VERSION 5.7 ;
  NOWIREEXTENSIONATPIN ON ;
  DIVIDERCHAR "/" ;
  BUSBITCHARS "[]" ;
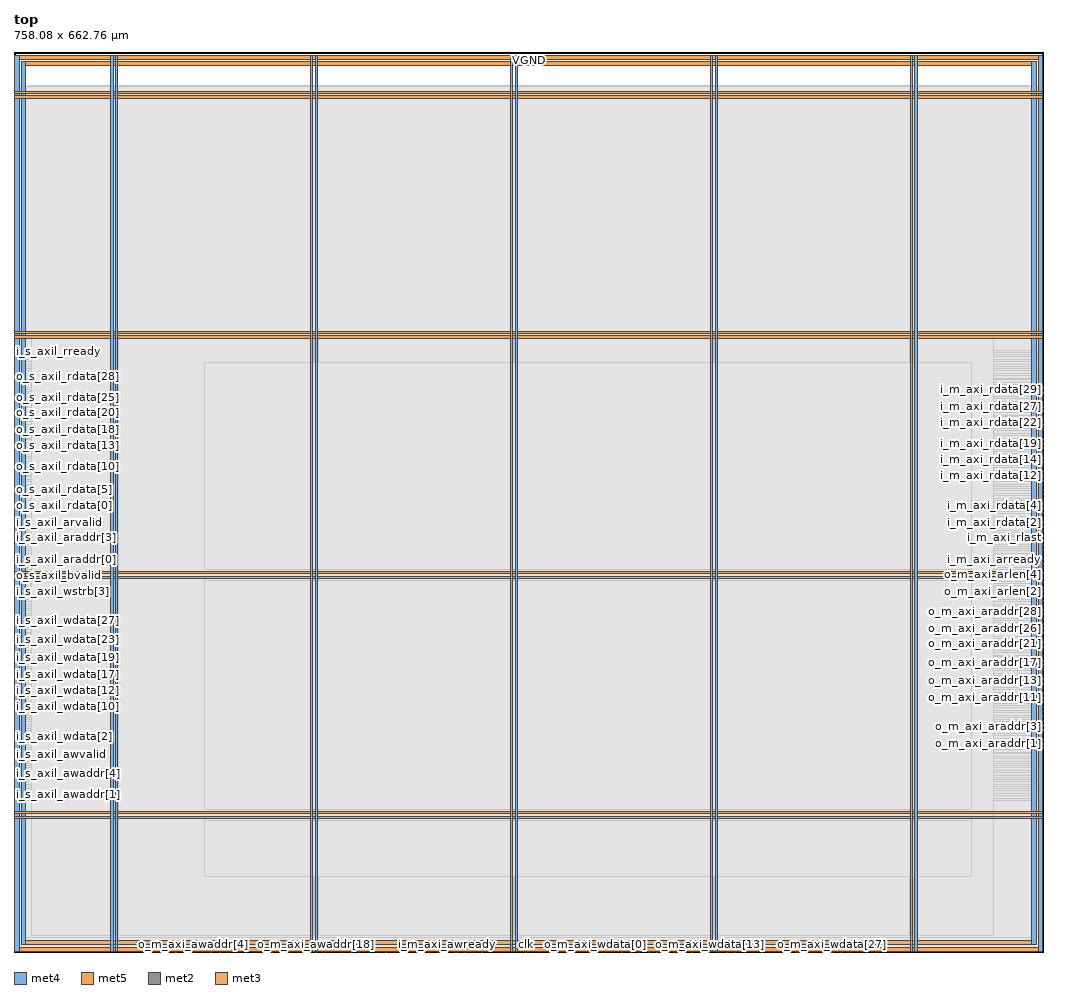
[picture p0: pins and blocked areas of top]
MACRO top
  CLASS BLOCK ;
  FOREIGN top ;
  ORIGIN 0.000 0.000 ;
  SIZE 758.080 BY 662.760 ;
  PIN VGND
    DIRECTION INOUT ;
    USE GROUND ;
    PORT
      LAYER met4 ;
        RECT 0.640 0.480 3.740 660.480 ;
    END
    PORT
      LAYER met4 ;
        RECT 754.340 0.480 757.440 660.480 ;
    END
    PORT
      LAYER met5 ;
        RECT 0.640 0.480 757.440 3.580 ;
    END
    PORT
      LAYER met5 ;
        RECT 0.640 657.380 757.440 660.480 ;
    END
    PORT
      LAYER met4 ;
        RECT 74.675 0.480 76.275 660.480 ;
    END
    PORT
      LAYER met4 ;
        RECT 221.875 0.480 223.475 660.480 ;
    END
    PORT
      LAYER met4 ;
        RECT 369.075 0.480 370.675 660.480 ;
    END
    PORT
      LAYER met4 ;
        RECT 516.275 0.480 517.875 660.480 ;
    END
    PORT
      LAYER met4 ;
        RECT 663.475 0.480 665.075 660.480 ;
    END
    PORT
      LAYER met5 ;
        RECT 0.640 101.780 757.440 103.380 ;
    END
    PORT
      LAYER met5 ;
        RECT 0.640 278.580 757.440 280.180 ;
    END
    PORT
      LAYER met5 ;
        RECT 0.640 455.380 757.440 456.980 ;
    END
    PORT
      LAYER met5 ;
        RECT 0.640 632.180 757.440 633.780 ;
    END
  END VGND
  PIN VPWR
    DIRECTION INOUT ;
    USE POWER ;
    PORT
      LAYER met4 ;
        RECT 5.440 5.280 8.540 655.680 ;
    END
    PORT
      LAYER met4 ;
        RECT 749.540 5.280 752.640 655.680 ;
    END
    PORT
      LAYER met5 ;
        RECT 5.440 5.280 752.640 8.380 ;
    END
    PORT
      LAYER met5 ;
        RECT 5.440 652.580 752.640 655.680 ;
    END
    PORT
      LAYER met4 ;
        RECT 71.375 0.480 72.975 660.480 ;
    END
    PORT
      LAYER met4 ;
        RECT 218.575 0.480 220.175 660.480 ;
    END
    PORT
      LAYER met4 ;
        RECT 365.775 0.480 367.375 660.480 ;
    END
    PORT
      LAYER met4 ;
        RECT 512.975 0.480 514.575 660.480 ;
    END
    PORT
      LAYER met4 ;
        RECT 660.175 0.480 661.775 660.480 ;
    END
    PORT
      LAYER met5 ;
        RECT 0.640 98.480 757.440 100.080 ;
    END
    PORT
      LAYER met5 ;
        RECT 0.640 275.280 757.440 276.880 ;
    END
    PORT
      LAYER met5 ;
        RECT 0.640 452.080 757.440 453.680 ;
    END
    PORT
      LAYER met5 ;
        RECT 0.640 628.880 757.440 630.480 ;
    END
  END VPWR
  PIN clk
    DIRECTION INPUT ;
    USE SIGNAL ;
    ANTENNAGATEAREA 1.704000 ;
    PORT
      LAYER met2 ;
        RECT 376.830 0.000 377.110 0.280 ;
    END
  END clk
  PIN i_m_axi_arready
    DIRECTION INPUT ;
    USE SIGNAL ;
    ANTENNAGATEAREA 0.196500 ;
    PORT
      LAYER met3 ;
        RECT 757.480 289.040 758.080 289.640 ;
    END
  END i_m_axi_arready
  PIN i_m_axi_awready
    DIRECTION INPUT ;
    USE SIGNAL ;
    ANTENNAGATEAREA 0.196500 ;
    PORT
      LAYER met2 ;
        RECT 318.870 0.000 319.150 0.280 ;
    END
  END i_m_axi_awready
  PIN i_m_axi_bresp[0]
    DIRECTION INPUT ;
    USE SIGNAL ;
    ANTENNAGATEAREA 0.196500 ;
    PORT
      LAYER met2 ;
        RECT 325.310 0.000 325.590 0.280 ;
    END
  END i_m_axi_bresp[0]
  PIN i_m_axi_bresp[1]
    DIRECTION INPUT ;
    USE SIGNAL ;
    ANTENNAGATEAREA 0.196500 ;
    PORT
      LAYER met2 ;
        RECT 331.750 0.000 332.030 0.280 ;
    END
  END i_m_axi_bresp[1]
  PIN i_m_axi_bvalid
    DIRECTION INPUT ;
    USE SIGNAL ;
    ANTENNAGATEAREA 0.196500 ;
    PORT
      LAYER met2 ;
        RECT 338.190 0.000 338.470 0.280 ;
    END
  END i_m_axi_bvalid
  PIN i_m_axi_rdata[0]
    DIRECTION INPUT ;
    USE SIGNAL ;
    ANTENNAGATEAREA 0.196500 ;
    PORT
      LAYER met3 ;
        RECT 757.480 309.440 758.080 310.040 ;
    END
  END i_m_axi_rdata[0]
  PIN i_m_axi_rdata[10]
    DIRECTION INPUT ;
    USE SIGNAL ;
    ANTENNAGATEAREA 0.196500 ;
    PORT
      LAYER met3 ;
        RECT 757.480 343.440 758.080 344.040 ;
    END
  END i_m_axi_rdata[10]
  PIN i_m_axi_rdata[11]
    DIRECTION INPUT ;
    USE SIGNAL ;
    ANTENNAGATEAREA 0.196500 ;
    PORT
      LAYER met3 ;
        RECT 757.480 346.840 758.080 347.440 ;
    END
  END i_m_axi_rdata[11]
  PIN i_m_axi_rdata[12]
    DIRECTION INPUT ;
    USE SIGNAL ;
    ANTENNAGATEAREA 0.196500 ;
    PORT
      LAYER met3 ;
        RECT 757.480 350.240 758.080 350.840 ;
    END
  END i_m_axi_rdata[12]
  PIN i_m_axi_rdata[13]
    DIRECTION INPUT ;
    USE SIGNAL ;
    ANTENNAGATEAREA 0.196500 ;
    PORT
      LAYER met3 ;
        RECT 757.480 353.640 758.080 354.240 ;
    END
  END i_m_axi_rdata[13]
  PIN i_m_axi_rdata[14]
    DIRECTION INPUT ;
    USE SIGNAL ;
    ANTENNAGATEAREA 0.196500 ;
    PORT
      LAYER met3 ;
        RECT 757.480 357.040 758.080 357.640 ;
    END
  END i_m_axi_rdata[14]
  PIN i_m_axi_rdata[15]
    DIRECTION INPUT ;
    USE SIGNAL ;
    ANTENNAGATEAREA 0.196500 ;
    PORT
      LAYER met3 ;
        RECT 757.480 360.440 758.080 361.040 ;
    END
  END i_m_axi_rdata[15]
  PIN i_m_axi_rdata[16]
    DIRECTION INPUT ;
    USE SIGNAL ;
    ANTENNAGATEAREA 0.196500 ;
    PORT
      LAYER met3 ;
        RECT 757.480 363.840 758.080 364.440 ;
    END
  END i_m_axi_rdata[16]
  PIN i_m_axi_rdata[17]
    DIRECTION INPUT ;
    USE SIGNAL ;
    ANTENNAGATEAREA 0.196500 ;
    PORT
      LAYER met3 ;
        RECT 757.480 367.240 758.080 367.840 ;
    END
  END i_m_axi_rdata[17]
  PIN i_m_axi_rdata[18]
    DIRECTION INPUT ;
    USE SIGNAL ;
    ANTENNAGATEAREA 0.196500 ;
    PORT
      LAYER met3 ;
        RECT 757.480 370.640 758.080 371.240 ;
    END
  END i_m_axi_rdata[18]
  PIN i_m_axi_rdata[19]
    DIRECTION INPUT ;
    USE SIGNAL ;
    ANTENNAGATEAREA 0.196500 ;
    PORT
      LAYER met3 ;
        RECT 757.480 374.040 758.080 374.640 ;
    END
  END i_m_axi_rdata[19]
  PIN i_m_axi_rdata[1]
    DIRECTION INPUT ;
    USE SIGNAL ;
    ANTENNAGATEAREA 0.196500 ;
    PORT
      LAYER met3 ;
        RECT 757.480 312.840 758.080 313.440 ;
    END
  END i_m_axi_rdata[1]
  PIN i_m_axi_rdata[20]
    DIRECTION INPUT ;
    USE SIGNAL ;
    ANTENNAGATEAREA 0.196500 ;
    PORT
      LAYER met3 ;
        RECT 757.480 377.440 758.080 378.040 ;
    END
  END i_m_axi_rdata[20]
  PIN i_m_axi_rdata[21]
    DIRECTION INPUT ;
    USE SIGNAL ;
    ANTENNAGATEAREA 0.196500 ;
    PORT
      LAYER met3 ;
        RECT 757.480 380.840 758.080 381.440 ;
    END
  END i_m_axi_rdata[21]
  PIN i_m_axi_rdata[22]
    DIRECTION INPUT ;
    USE SIGNAL ;
    ANTENNAGATEAREA 0.196500 ;
    PORT
      LAYER met3 ;
        RECT 757.480 384.240 758.080 384.840 ;
    END
  END i_m_axi_rdata[22]
  PIN i_m_axi_rdata[23]
    DIRECTION INPUT ;
    USE SIGNAL ;
    ANTENNAGATEAREA 0.196500 ;
    PORT
      LAYER met3 ;
        RECT 757.480 387.640 758.080 388.240 ;
    END
  END i_m_axi_rdata[23]
  PIN i_m_axi_rdata[24]
    DIRECTION INPUT ;
    USE SIGNAL ;
    ANTENNAGATEAREA 0.196500 ;
    PORT
      LAYER met3 ;
        RECT 757.480 391.040 758.080 391.640 ;
    END
  END i_m_axi_rdata[24]
  PIN i_m_axi_rdata[25]
    DIRECTION INPUT ;
    USE SIGNAL ;
    ANTENNAGATEAREA 0.196500 ;
    PORT
      LAYER met3 ;
        RECT 757.480 394.440 758.080 395.040 ;
    END
  END i_m_axi_rdata[25]
  PIN i_m_axi_rdata[26]
    DIRECTION INPUT ;
    USE SIGNAL ;
    ANTENNAGATEAREA 0.196500 ;
    PORT
      LAYER met3 ;
        RECT 757.480 397.840 758.080 398.440 ;
    END
  END i_m_axi_rdata[26]
  PIN i_m_axi_rdata[27]
    DIRECTION INPUT ;
    USE SIGNAL ;
    ANTENNAGATEAREA 0.196500 ;
    PORT
      LAYER met3 ;
        RECT 757.480 401.240 758.080 401.840 ;
    END
  END i_m_axi_rdata[27]
  PIN i_m_axi_rdata[28]
    DIRECTION INPUT ;
    USE SIGNAL ;
    ANTENNAGATEAREA 0.196500 ;
    PORT
      LAYER met3 ;
        RECT 757.480 404.640 758.080 405.240 ;
    END
  END i_m_axi_rdata[28]
  PIN i_m_axi_rdata[29]
    DIRECTION INPUT ;
    USE SIGNAL ;
    ANTENNAGATEAREA 0.196500 ;
    PORT
      LAYER met3 ;
        RECT 757.480 408.040 758.080 408.640 ;
    END
  END i_m_axi_rdata[29]
  PIN i_m_axi_rdata[2]
    DIRECTION INPUT ;
    USE SIGNAL ;
    ANTENNAGATEAREA 0.196500 ;
    PORT
      LAYER met3 ;
        RECT 757.480 316.240 758.080 316.840 ;
    END
  END i_m_axi_rdata[2]
  PIN i_m_axi_rdata[30]
    DIRECTION INPUT ;
    USE SIGNAL ;
    ANTENNAGATEAREA 0.196500 ;
    PORT
      LAYER met3 ;
        RECT 757.480 411.440 758.080 412.040 ;
    END
  END i_m_axi_rdata[30]
  PIN i_m_axi_rdata[31]
    DIRECTION INPUT ;
    USE SIGNAL ;
    ANTENNAGATEAREA 0.196500 ;
    PORT
      LAYER met3 ;
        RECT 757.480 414.840 758.080 415.440 ;
    END
  END i_m_axi_rdata[31]
  PIN i_m_axi_rdata[3]
    DIRECTION INPUT ;
    USE SIGNAL ;
    ANTENNAGATEAREA 0.196500 ;
    PORT
      LAYER met3 ;
        RECT 757.480 319.640 758.080 320.240 ;
    END
  END i_m_axi_rdata[3]
  PIN i_m_axi_rdata[4]
    DIRECTION INPUT ;
    USE SIGNAL ;
    ANTENNAGATEAREA 0.196500 ;
    PORT
      LAYER met3 ;
        RECT 757.480 323.040 758.080 323.640 ;
    END
  END i_m_axi_rdata[4]
  PIN i_m_axi_rdata[5]
    DIRECTION INPUT ;
    USE SIGNAL ;
    ANTENNAGATEAREA 0.196500 ;
    PORT
      LAYER met3 ;
        RECT 757.480 326.440 758.080 327.040 ;
    END
  END i_m_axi_rdata[5]
  PIN i_m_axi_rdata[6]
    DIRECTION INPUT ;
    USE SIGNAL ;
    ANTENNAGATEAREA 0.196500 ;
    PORT
      LAYER met3 ;
        RECT 757.480 329.840 758.080 330.440 ;
    END
  END i_m_axi_rdata[6]
  PIN i_m_axi_rdata[7]
    DIRECTION INPUT ;
    USE SIGNAL ;
    ANTENNAGATEAREA 0.196500 ;
    PORT
      LAYER met3 ;
        RECT 757.480 333.240 758.080 333.840 ;
    END
  END i_m_axi_rdata[7]
  PIN i_m_axi_rdata[8]
    DIRECTION INPUT ;
    USE SIGNAL ;
    ANTENNAGATEAREA 0.196500 ;
    PORT
      LAYER met3 ;
        RECT 757.480 336.640 758.080 337.240 ;
    END
  END i_m_axi_rdata[8]
  PIN i_m_axi_rdata[9]
    DIRECTION INPUT ;
    USE SIGNAL ;
    ANTENNAGATEAREA 0.196500 ;
    PORT
      LAYER met3 ;
        RECT 757.480 340.040 758.080 340.640 ;
    END
  END i_m_axi_rdata[9]
  PIN i_m_axi_rlast
    DIRECTION INPUT ;
    USE SIGNAL ;
    ANTENNAGATEAREA 0.196500 ;
    PORT
      LAYER met3 ;
        RECT 757.480 299.240 758.080 299.840 ;
    END
  END i_m_axi_rlast
  PIN i_m_axi_rresp[0]
    DIRECTION INPUT ;
    USE SIGNAL ;
    ANTENNAGATEAREA 0.196500 ;
    PORT
      LAYER met3 ;
        RECT 757.480 302.640 758.080 303.240 ;
    END
  END i_m_axi_rresp[0]
  PIN i_m_axi_rresp[1]
    DIRECTION INPUT ;
    USE SIGNAL ;
    ANTENNAGATEAREA 0.196500 ;
    PORT
      LAYER met3 ;
        RECT 757.480 306.040 758.080 306.640 ;
    END
  END i_m_axi_rresp[1]
  PIN i_m_axi_rvalid
    DIRECTION INPUT ;
    USE SIGNAL ;
    ANTENNAGATEAREA 0.196500 ;
    PORT
      LAYER met3 ;
        RECT 757.480 295.840 758.080 296.440 ;
    END
  END i_m_axi_rvalid
  PIN i_m_axi_wready
    DIRECTION INPUT ;
    USE SIGNAL ;
    ANTENNAGATEAREA 0.196500 ;
    PORT
      LAYER met2 ;
        RECT 647.310 0.000 647.590 0.280 ;
    END
  END i_m_axi_wready
  PIN i_s_axil_araddr[0]
    DIRECTION INPUT ;
    USE SIGNAL ;
    PORT
      LAYER met3 ;
        RECT 0.000 289.040 0.600 289.640 ;
    END
  END i_s_axil_araddr[0]
  PIN i_s_axil_araddr[1]
    DIRECTION INPUT ;
    USE SIGNAL ;
    PORT
      LAYER met3 ;
        RECT 0.000 292.440 0.600 293.040 ;
    END
  END i_s_axil_araddr[1]
  PIN i_s_axil_araddr[2]
    DIRECTION INPUT ;
    USE SIGNAL ;
    ANTENNAGATEAREA 0.196500 ;
    PORT
      LAYER met3 ;
        RECT 0.000 295.840 0.600 296.440 ;
    END
  END i_s_axil_araddr[2]
  PIN i_s_axil_araddr[3]
    DIRECTION INPUT ;
    USE SIGNAL ;
    ANTENNAGATEAREA 0.196500 ;
    PORT
      LAYER met3 ;
        RECT 0.000 299.240 0.600 299.840 ;
    END
  END i_s_axil_araddr[3]
  PIN i_s_axil_araddr[4]
    DIRECTION INPUT ;
    USE SIGNAL ;
    ANTENNAGATEAREA 0.196500 ;
    PORT
      LAYER met3 ;
        RECT 0.000 302.640 0.600 303.240 ;
    END
  END i_s_axil_araddr[4]
  PIN i_s_axil_araddr[5]
    DIRECTION INPUT ;
    USE SIGNAL ;
    ANTENNAGATEAREA 0.196500 ;
    PORT
      LAYER met3 ;
        RECT 0.000 306.040 0.600 306.640 ;
    END
  END i_s_axil_araddr[5]
  PIN i_s_axil_araddr[6]
    DIRECTION INPUT ;
    USE SIGNAL ;
    ANTENNAGATEAREA 0.196500 ;
    PORT
      LAYER met3 ;
        RECT 0.000 309.440 0.600 310.040 ;
    END
  END i_s_axil_araddr[6]
  PIN i_s_axil_araddr[7]
    DIRECTION INPUT ;
    USE SIGNAL ;
    ANTENNAGATEAREA 0.196500 ;
    PORT
      LAYER met3 ;
        RECT 0.000 312.840 0.600 313.440 ;
    END
  END i_s_axil_araddr[7]
  PIN i_s_axil_arvalid
    DIRECTION INPUT ;
    USE SIGNAL ;
    ANTENNAGATEAREA 0.196500 ;
    PORT
      LAYER met3 ;
        RECT 0.000 316.240 0.600 316.840 ;
    END
  END i_s_axil_arvalid
  PIN i_s_axil_awaddr[0]
    DIRECTION INPUT ;
    USE SIGNAL ;
    PORT
      LAYER met3 ;
        RECT 0.000 112.240 0.600 112.840 ;
    END
  END i_s_axil_awaddr[0]
  PIN i_s_axil_awaddr[1]
    DIRECTION INPUT ;
    USE SIGNAL ;
    PORT
      LAYER met3 ;
        RECT 0.000 115.640 0.600 116.240 ;
    END
  END i_s_axil_awaddr[1]
  PIN i_s_axil_awaddr[2]
    DIRECTION INPUT ;
    USE SIGNAL ;
    ANTENNAGATEAREA 0.196500 ;
    PORT
      LAYER met3 ;
        RECT 0.000 119.040 0.600 119.640 ;
    END
  END i_s_axil_awaddr[2]
  PIN i_s_axil_awaddr[3]
    DIRECTION INPUT ;
    USE SIGNAL ;
    ANTENNAGATEAREA 0.196500 ;
    PORT
      LAYER met3 ;
        RECT 0.000 122.440 0.600 123.040 ;
    END
  END i_s_axil_awaddr[3]
  PIN i_s_axil_awaddr[4]
    DIRECTION INPUT ;
    USE SIGNAL ;
    ANTENNAGATEAREA 0.196500 ;
    PORT
      LAYER met3 ;
        RECT 0.000 125.840 0.600 126.440 ;
    END
  END i_s_axil_awaddr[4]
  PIN i_s_axil_awaddr[5]
    DIRECTION INPUT ;
    USE SIGNAL ;
    ANTENNAGATEAREA 0.196500 ;
    PORT
      LAYER met3 ;
        RECT 0.000 129.240 0.600 129.840 ;
    END
  END i_s_axil_awaddr[5]
  PIN i_s_axil_awaddr[6]
    DIRECTION INPUT ;
    USE SIGNAL ;
    ANTENNAGATEAREA 0.196500 ;
    PORT
      LAYER met3 ;
        RECT 0.000 132.640 0.600 133.240 ;
    END
  END i_s_axil_awaddr[6]
  PIN i_s_axil_awaddr[7]
    DIRECTION INPUT ;
    USE SIGNAL ;
    ANTENNAGATEAREA 0.196500 ;
    PORT
      LAYER met3 ;
        RECT 0.000 136.040 0.600 136.640 ;
    END
  END i_s_axil_awaddr[7]
  PIN i_s_axil_awvalid
    DIRECTION INPUT ;
    USE SIGNAL ;
    ANTENNAGATEAREA 0.196500 ;
    PORT
      LAYER met3 ;
        RECT 0.000 139.440 0.600 140.040 ;
    END
  END i_s_axil_awvalid
  PIN i_s_axil_bready
    DIRECTION INPUT ;
    USE SIGNAL ;
    ANTENNAGATEAREA 0.196500 ;
    PORT
      LAYER met3 ;
        RECT 0.000 285.640 0.600 286.240 ;
    END
  END i_s_axil_bready
  PIN i_s_axil_rready
    DIRECTION INPUT ;
    USE SIGNAL ;
    ANTENNAGATEAREA 0.196500 ;
    PORT
      LAYER met3 ;
        RECT 0.000 442.040 0.600 442.640 ;
    END
  END i_s_axil_rready
  PIN i_s_axil_wdata[0]
    DIRECTION INPUT ;
    USE SIGNAL ;
    ANTENNAGATEAREA 0.196500 ;
    PORT
      LAYER met3 ;
        RECT 0.000 146.240 0.600 146.840 ;
    END
  END i_s_axil_wdata[0]
  PIN i_s_axil_wdata[10]
    DIRECTION INPUT ;
    USE SIGNAL ;
    ANTENNAGATEAREA 0.196500 ;
    PORT
      LAYER met3 ;
        RECT 0.000 180.240 0.600 180.840 ;
    END
  END i_s_axil_wdata[10]
  PIN i_s_axil_wdata[11]
    DIRECTION INPUT ;
    USE SIGNAL ;
    ANTENNAGATEAREA 0.196500 ;
    PORT
      LAYER met3 ;
        RECT 0.000 183.640 0.600 184.240 ;
    END
  END i_s_axil_wdata[11]
  PIN i_s_axil_wdata[12]
    DIRECTION INPUT ;
    USE SIGNAL ;
    ANTENNAGATEAREA 0.196500 ;
    PORT
      LAYER met3 ;
        RECT 0.000 187.040 0.600 187.640 ;
    END
  END i_s_axil_wdata[12]
  PIN i_s_axil_wdata[13]
    DIRECTION INPUT ;
    USE SIGNAL ;
    ANTENNAGATEAREA 0.196500 ;
    PORT
      LAYER met3 ;
        RECT 0.000 190.440 0.600 191.040 ;
    END
  END i_s_axil_wdata[13]
  PIN i_s_axil_wdata[14]
    DIRECTION INPUT ;
    USE SIGNAL ;
    ANTENNAGATEAREA 0.196500 ;
    PORT
      LAYER met3 ;
        RECT 0.000 193.840 0.600 194.440 ;
    END
  END i_s_axil_wdata[14]
  PIN i_s_axil_wdata[15]
    DIRECTION INPUT ;
    USE SIGNAL ;
    ANTENNAGATEAREA 0.196500 ;
    PORT
      LAYER met3 ;
        RECT 0.000 197.240 0.600 197.840 ;
    END
  END i_s_axil_wdata[15]
  PIN i_s_axil_wdata[16]
    DIRECTION INPUT ;
    USE SIGNAL ;
    ANTENNAGATEAREA 0.196500 ;
    PORT
      LAYER met3 ;
        RECT 0.000 200.640 0.600 201.240 ;
    END
  END i_s_axil_wdata[16]
  PIN i_s_axil_wdata[17]
    DIRECTION INPUT ;
    USE SIGNAL ;
    ANTENNAGATEAREA 0.196500 ;
    PORT
      LAYER met3 ;
        RECT 0.000 204.040 0.600 204.640 ;
    END
  END i_s_axil_wdata[17]
  PIN i_s_axil_wdata[18]
    DIRECTION INPUT ;
    USE SIGNAL ;
    ANTENNAGATEAREA 0.196500 ;
    PORT
      LAYER met3 ;
        RECT 0.000 207.440 0.600 208.040 ;
    END
  END i_s_axil_wdata[18]
  PIN i_s_axil_wdata[19]
    DIRECTION INPUT ;
    USE SIGNAL ;
    ANTENNAGATEAREA 0.196500 ;
    PORT
      LAYER met3 ;
        RECT 0.000 210.840 0.600 211.440 ;
    END
  END i_s_axil_wdata[19]
  PIN i_s_axil_wdata[1]
    DIRECTION INPUT ;
    USE SIGNAL ;
    ANTENNAGATEAREA 0.196500 ;
    PORT
      LAYER met3 ;
        RECT 0.000 149.640 0.600 150.240 ;
    END
  END i_s_axil_wdata[1]
  PIN i_s_axil_wdata[20]
    DIRECTION INPUT ;
    USE SIGNAL ;
    ANTENNAGATEAREA 0.196500 ;
    PORT
      LAYER met3 ;
        RECT 0.000 214.240 0.600 214.840 ;
    END
  END i_s_axil_wdata[20]
  PIN i_s_axil_wdata[21]
    DIRECTION INPUT ;
    USE SIGNAL ;
    ANTENNAGATEAREA 0.196500 ;
    PORT
      LAYER met3 ;
        RECT 0.000 217.640 0.600 218.240 ;
    END
  END i_s_axil_wdata[21]
  PIN i_s_axil_wdata[22]
    DIRECTION INPUT ;
    USE SIGNAL ;
    ANTENNAGATEAREA 0.196500 ;
    PORT
      LAYER met3 ;
        RECT 0.000 221.040 0.600 221.640 ;
    END
  END i_s_axil_wdata[22]
  PIN i_s_axil_wdata[23]
    DIRECTION INPUT ;
    USE SIGNAL ;
    ANTENNAGATEAREA 0.196500 ;
    PORT
      LAYER met3 ;
        RECT 0.000 224.440 0.600 225.040 ;
    END
  END i_s_axil_wdata[23]
  PIN i_s_axil_wdata[24]
    DIRECTION INPUT ;
    USE SIGNAL ;
    ANTENNAGATEAREA 0.196500 ;
    PORT
      LAYER met3 ;
        RECT 0.000 227.840 0.600 228.440 ;
    END
  END i_s_axil_wdata[24]
  PIN i_s_axil_wdata[25]
    DIRECTION INPUT ;
    USE SIGNAL ;
    ANTENNAGATEAREA 0.196500 ;
    PORT
      LAYER met3 ;
        RECT 0.000 231.240 0.600 231.840 ;
    END
  END i_s_axil_wdata[25]
  PIN i_s_axil_wdata[26]
    DIRECTION INPUT ;
    USE SIGNAL ;
    ANTENNAGATEAREA 0.196500 ;
    PORT
      LAYER met3 ;
        RECT 0.000 234.640 0.600 235.240 ;
    END
  END i_s_axil_wdata[26]
  PIN i_s_axil_wdata[27]
    DIRECTION INPUT ;
    USE SIGNAL ;
    ANTENNAGATEAREA 0.196500 ;
    PORT
      LAYER met3 ;
        RECT 0.000 238.040 0.600 238.640 ;
    END
  END i_s_axil_wdata[27]
  PIN i_s_axil_wdata[28]
    DIRECTION INPUT ;
    USE SIGNAL ;
    ANTENNAGATEAREA 0.196500 ;
    PORT
      LAYER met3 ;
        RECT 0.000 241.440 0.600 242.040 ;
    END
  END i_s_axil_wdata[28]
  PIN i_s_axil_wdata[29]
    DIRECTION INPUT ;
    USE SIGNAL ;
    ANTENNAGATEAREA 0.196500 ;
    PORT
      LAYER met3 ;
        RECT 0.000 244.840 0.600 245.440 ;
    END
  END i_s_axil_wdata[29]
  PIN i_s_axil_wdata[2]
    DIRECTION INPUT ;
    USE SIGNAL ;
    ANTENNAGATEAREA 0.196500 ;
    PORT
      LAYER met3 ;
        RECT 0.000 153.040 0.600 153.640 ;
    END
  END i_s_axil_wdata[2]
  PIN i_s_axil_wdata[30]
    DIRECTION INPUT ;
    USE SIGNAL ;
    ANTENNAGATEAREA 0.196500 ;
    PORT
      LAYER met3 ;
        RECT 0.000 248.240 0.600 248.840 ;
    END
  END i_s_axil_wdata[30]
  PIN i_s_axil_wdata[31]
    DIRECTION INPUT ;
    USE SIGNAL ;
    ANTENNAGATEAREA 0.196500 ;
    PORT
      LAYER met3 ;
        RECT 0.000 251.640 0.600 252.240 ;
    END
  END i_s_axil_wdata[31]
  PIN i_s_axil_wdata[3]
    DIRECTION INPUT ;
    USE SIGNAL ;
    ANTENNAGATEAREA 0.196500 ;
    PORT
      LAYER met3 ;
        RECT 0.000 156.440 0.600 157.040 ;
    END
  END i_s_axil_wdata[3]
  PIN i_s_axil_wdata[4]
    DIRECTION INPUT ;
    USE SIGNAL ;
    ANTENNAGATEAREA 0.196500 ;
    PORT
      LAYER met3 ;
        RECT 0.000 159.840 0.600 160.440 ;
    END
  END i_s_axil_wdata[4]
  PIN i_s_axil_wdata[5]
    DIRECTION INPUT ;
    USE SIGNAL ;
    ANTENNAGATEAREA 0.196500 ;
    PORT
      LAYER met3 ;
        RECT 0.000 163.240 0.600 163.840 ;
    END
  END i_s_axil_wdata[5]
  PIN i_s_axil_wdata[6]
    DIRECTION INPUT ;
    USE SIGNAL ;
    ANTENNAGATEAREA 0.196500 ;
    PORT
      LAYER met3 ;
        RECT 0.000 166.640 0.600 167.240 ;
    END
  END i_s_axil_wdata[6]
  PIN i_s_axil_wdata[7]
    DIRECTION INPUT ;
    USE SIGNAL ;
    ANTENNAGATEAREA 0.196500 ;
    PORT
      LAYER met3 ;
        RECT 0.000 170.040 0.600 170.640 ;
    END
  END i_s_axil_wdata[7]
  PIN i_s_axil_wdata[8]
    DIRECTION INPUT ;
    USE SIGNAL ;
    ANTENNAGATEAREA 0.196500 ;
    PORT
      LAYER met3 ;
        RECT 0.000 173.440 0.600 174.040 ;
    END
  END i_s_axil_wdata[8]
  PIN i_s_axil_wdata[9]
    DIRECTION INPUT ;
    USE SIGNAL ;
    ANTENNAGATEAREA 0.196500 ;
    PORT
      LAYER met3 ;
        RECT 0.000 176.840 0.600 177.440 ;
    END
  END i_s_axil_wdata[9]
  PIN i_s_axil_wstrb[0]
    DIRECTION INPUT ;
    USE SIGNAL ;
    ANTENNAGATEAREA 0.196500 ;
    PORT
      LAYER met3 ;
        RECT 0.000 255.040 0.600 255.640 ;
    END
  END i_s_axil_wstrb[0]
  PIN i_s_axil_wstrb[1]
    DIRECTION INPUT ;
    USE SIGNAL ;
    ANTENNAGATEAREA 0.196500 ;
    PORT
      LAYER met3 ;
        RECT 0.000 258.440 0.600 259.040 ;
    END
  END i_s_axil_wstrb[1]
  PIN i_s_axil_wstrb[2]
    DIRECTION INPUT ;
    USE SIGNAL ;
    ANTENNAGATEAREA 0.196500 ;
    PORT
      LAYER met3 ;
        RECT 0.000 261.840 0.600 262.440 ;
    END
  END i_s_axil_wstrb[2]
  PIN i_s_axil_wstrb[3]
    DIRECTION INPUT ;
    USE SIGNAL ;
    ANTENNAGATEAREA 0.196500 ;
    PORT
      LAYER met3 ;
        RECT 0.000 265.240 0.600 265.840 ;
    END
  END i_s_axil_wstrb[3]
  PIN i_s_axil_wvalid
    DIRECTION INPUT ;
    USE SIGNAL ;
    ANTENNAGATEAREA 0.196500 ;
    PORT
      LAYER met3 ;
        RECT 0.000 268.640 0.600 269.240 ;
    END
  END i_s_axil_wvalid
  PIN o_m_axi_araddr[0]
    DIRECTION OUTPUT ;
    USE SIGNAL ;
    PORT
      LAYER met3 ;
        RECT 757.480 149.640 758.080 150.240 ;
    END
  END o_m_axi_araddr[0]
  PIN o_m_axi_araddr[10]
    DIRECTION OUTPUT ;
    USE SIGNAL ;
    ANTENNADIFFAREA 0.340600 ;
    PORT
      LAYER met3 ;
        RECT 757.480 183.640 758.080 184.240 ;
    END
  END o_m_axi_araddr[10]
  PIN o_m_axi_araddr[11]
    DIRECTION OUTPUT ;
    USE SIGNAL ;
    ANTENNADIFFAREA 0.340600 ;
    PORT
      LAYER met3 ;
        RECT 757.480 187.040 758.080 187.640 ;
    END
  END o_m_axi_araddr[11]
  PIN o_m_axi_araddr[12]
    DIRECTION OUTPUT ;
    USE SIGNAL ;
    ANTENNADIFFAREA 0.340600 ;
    PORT
      LAYER met3 ;
        RECT 757.480 190.440 758.080 191.040 ;
    END
  END o_m_axi_araddr[12]
  PIN o_m_axi_araddr[13]
    DIRECTION OUTPUT ;
    USE SIGNAL ;
    ANTENNADIFFAREA 0.340600 ;
    PORT
      LAYER met3 ;
        RECT 757.480 193.840 758.080 194.440 ;
    END
  END o_m_axi_araddr[13]
  PIN o_m_axi_araddr[14]
    DIRECTION OUTPUT ;
    USE SIGNAL ;
    ANTENNADIFFAREA 0.340600 ;
    PORT
      LAYER met3 ;
        RECT 757.480 197.240 758.080 197.840 ;
    END
  END o_m_axi_araddr[14]
  PIN o_m_axi_araddr[15]
    DIRECTION OUTPUT ;
    USE SIGNAL ;
    ANTENNADIFFAREA 0.340600 ;
    PORT
      LAYER met3 ;
        RECT 757.480 200.640 758.080 201.240 ;
    END
  END o_m_axi_araddr[15]
  PIN o_m_axi_araddr[16]
    DIRECTION OUTPUT ;
    USE SIGNAL ;
    ANTENNADIFFAREA 0.340600 ;
    PORT
      LAYER met3 ;
        RECT 757.480 204.040 758.080 204.640 ;
    END
  END o_m_axi_araddr[16]
  PIN o_m_axi_araddr[17]
    DIRECTION OUTPUT ;
    USE SIGNAL ;
    ANTENNADIFFAREA 0.340600 ;
    PORT
      LAYER met3 ;
        RECT 757.480 207.440 758.080 208.040 ;
    END
  END o_m_axi_araddr[17]
  PIN o_m_axi_araddr[18]
    DIRECTION OUTPUT ;
    USE SIGNAL ;
    ANTENNADIFFAREA 0.340600 ;
    PORT
      LAYER met3 ;
        RECT 757.480 210.840 758.080 211.440 ;
    END
  END o_m_axi_araddr[18]
  PIN o_m_axi_araddr[19]
    DIRECTION OUTPUT ;
    USE SIGNAL ;
    ANTENNADIFFAREA 0.340600 ;
    PORT
      LAYER met3 ;
        RECT 757.480 214.240 758.080 214.840 ;
    END
  END o_m_axi_araddr[19]
  PIN o_m_axi_araddr[1]
    DIRECTION OUTPUT ;
    USE SIGNAL ;
    PORT
      LAYER met3 ;
        RECT 757.480 153.040 758.080 153.640 ;
    END
  END o_m_axi_araddr[1]
  PIN o_m_axi_araddr[20]
    DIRECTION OUTPUT ;
    USE SIGNAL ;
    ANTENNADIFFAREA 0.340600 ;
    PORT
      LAYER met3 ;
        RECT 757.480 217.640 758.080 218.240 ;
    END
  END o_m_axi_araddr[20]
  PIN o_m_axi_araddr[21]
    DIRECTION OUTPUT ;
    USE SIGNAL ;
    ANTENNADIFFAREA 0.340600 ;
    PORT
      LAYER met3 ;
        RECT 757.480 221.040 758.080 221.640 ;
    END
  END o_m_axi_araddr[21]
  PIN o_m_axi_araddr[22]
    DIRECTION OUTPUT ;
    USE SIGNAL ;
    ANTENNADIFFAREA 0.340600 ;
    PORT
      LAYER met3 ;
        RECT 757.480 224.440 758.080 225.040 ;
    END
  END o_m_axi_araddr[22]
  PIN o_m_axi_araddr[23]
    DIRECTION OUTPUT ;
    USE SIGNAL ;
    ANTENNADIFFAREA 0.340600 ;
    PORT
      LAYER met3 ;
        RECT 757.480 227.840 758.080 228.440 ;
    END
  END o_m_axi_araddr[23]
  PIN o_m_axi_araddr[24]
    DIRECTION OUTPUT ;
    USE SIGNAL ;
    ANTENNADIFFAREA 0.340600 ;
    PORT
      LAYER met3 ;
        RECT 757.480 231.240 758.080 231.840 ;
    END
  END o_m_axi_araddr[24]
  PIN o_m_axi_araddr[25]
    DIRECTION OUTPUT ;
    USE SIGNAL ;
    ANTENNADIFFAREA 0.340600 ;
    PORT
      LAYER met3 ;
        RECT 757.480 234.640 758.080 235.240 ;
    END
  END o_m_axi_araddr[25]
  PIN o_m_axi_araddr[26]
    DIRECTION OUTPUT ;
    USE SIGNAL ;
    ANTENNADIFFAREA 0.340600 ;
    PORT
      LAYER met3 ;
        RECT 757.480 238.040 758.080 238.640 ;
    END
  END o_m_axi_araddr[26]
  PIN o_m_axi_araddr[27]
    DIRECTION OUTPUT ;
    USE SIGNAL ;
    ANTENNADIFFAREA 0.340600 ;
    PORT
      LAYER met3 ;
        RECT 757.480 241.440 758.080 242.040 ;
    END
  END o_m_axi_araddr[27]
  PIN o_m_axi_araddr[28]
    DIRECTION OUTPUT ;
    USE SIGNAL ;
    ANTENNADIFFAREA 0.340600 ;
    PORT
      LAYER met3 ;
        RECT 757.480 244.840 758.080 245.440 ;
    END
  END o_m_axi_araddr[28]
  PIN o_m_axi_araddr[29]
    DIRECTION OUTPUT ;
    USE SIGNAL ;
    ANTENNADIFFAREA 0.340600 ;
    PORT
      LAYER met3 ;
        RECT 757.480 248.240 758.080 248.840 ;
    END
  END o_m_axi_araddr[29]
  PIN o_m_axi_araddr[2]
    DIRECTION OUTPUT ;
    USE SIGNAL ;
    ANTENNADIFFAREA 0.340600 ;
    PORT
      LAYER met3 ;
        RECT 757.480 156.440 758.080 157.040 ;
    END
  END o_m_axi_araddr[2]
  PIN o_m_axi_araddr[30]
    DIRECTION OUTPUT ;
    USE SIGNAL ;
    ANTENNADIFFAREA 0.340600 ;
    PORT
      LAYER met3 ;
        RECT 757.480 251.640 758.080 252.240 ;
    END
  END o_m_axi_araddr[30]
  PIN o_m_axi_araddr[31]
    DIRECTION OUTPUT ;
    USE SIGNAL ;
    ANTENNADIFFAREA 0.340600 ;
    PORT
      LAYER met3 ;
        RECT 757.480 255.040 758.080 255.640 ;
    END
  END o_m_axi_araddr[31]
  PIN o_m_axi_araddr[3]
    DIRECTION OUTPUT ;
    USE SIGNAL ;
    ANTENNADIFFAREA 0.340600 ;
    PORT
      LAYER met3 ;
        RECT 757.480 159.840 758.080 160.440 ;
    END
  END o_m_axi_araddr[3]
  PIN o_m_axi_araddr[4]
    DIRECTION OUTPUT ;
    USE SIGNAL ;
    ANTENNADIFFAREA 0.340600 ;
    PORT
      LAYER met3 ;
        RECT 757.480 163.240 758.080 163.840 ;
    END
  END o_m_axi_araddr[4]
  PIN o_m_axi_araddr[5]
    DIRECTION OUTPUT ;
    USE SIGNAL ;
    ANTENNADIFFAREA 0.340600 ;
    PORT
      LAYER met3 ;
        RECT 757.480 166.640 758.080 167.240 ;
    END
  END o_m_axi_araddr[5]
  PIN o_m_axi_araddr[6]
    DIRECTION OUTPUT ;
    USE SIGNAL ;
    ANTENNADIFFAREA 0.340600 ;
    PORT
      LAYER met3 ;
        RECT 757.480 170.040 758.080 170.640 ;
    END
  END o_m_axi_araddr[6]
  PIN o_m_axi_araddr[7]
    DIRECTION OUTPUT ;
    USE SIGNAL ;
    ANTENNADIFFAREA 0.340600 ;
    PORT
      LAYER met3 ;
        RECT 757.480 173.440 758.080 174.040 ;
    END
  END o_m_axi_araddr[7]
  PIN o_m_axi_araddr[8]
    DIRECTION OUTPUT ;
    USE SIGNAL ;
    ANTENNADIFFAREA 0.340600 ;
    PORT
      LAYER met3 ;
        RECT 757.480 176.840 758.080 177.440 ;
    END
  END o_m_axi_araddr[8]
  PIN o_m_axi_araddr[9]
    DIRECTION OUTPUT ;
    USE SIGNAL ;
    ANTENNADIFFAREA 0.340600 ;
    PORT
      LAYER met3 ;
        RECT 757.480 180.240 758.080 180.840 ;
    END
  END o_m_axi_araddr[9]
  PIN o_m_axi_arlen[0]
    DIRECTION OUTPUT ;
    USE SIGNAL ;
    ANTENNADIFFAREA 0.340600 ;
    PORT
      LAYER met3 ;
        RECT 757.480 258.440 758.080 259.040 ;
    END
  END o_m_axi_arlen[0]
  PIN o_m_axi_arlen[1]
    DIRECTION OUTPUT ;
    USE SIGNAL ;
    ANTENNADIFFAREA 0.340600 ;
    PORT
      LAYER met3 ;
        RECT 757.480 261.840 758.080 262.440 ;
    END
  END o_m_axi_arlen[1]
  PIN o_m_axi_arlen[2]
    DIRECTION OUTPUT ;
    USE SIGNAL ;
    ANTENNADIFFAREA 0.340600 ;
    PORT
      LAYER met3 ;
        RECT 757.480 265.240 758.080 265.840 ;
    END
  END o_m_axi_arlen[2]
  PIN o_m_axi_arlen[3]
    DIRECTION OUTPUT ;
    USE SIGNAL ;
    ANTENNADIFFAREA 0.340600 ;
    PORT
      LAYER met3 ;
        RECT 757.480 268.640 758.080 269.240 ;
    END
  END o_m_axi_arlen[3]
  PIN o_m_axi_arlen[4]
    DIRECTION OUTPUT ;
    USE SIGNAL ;
    ANTENNADIFFAREA 0.340600 ;
    PORT
      LAYER met3 ;
        RECT 757.480 272.040 758.080 272.640 ;
    END
  END o_m_axi_arlen[4]
  PIN o_m_axi_arlen[5]
    DIRECTION OUTPUT ;
    USE SIGNAL ;
    ANTENNADIFFAREA 0.340600 ;
    PORT
      LAYER met3 ;
        RECT 757.480 275.440 758.080 276.040 ;
    END
  END o_m_axi_arlen[5]
  PIN o_m_axi_arlen[6]
    DIRECTION OUTPUT ;
    USE SIGNAL ;
    ANTENNADIFFAREA 0.340600 ;
    PORT
      LAYER met3 ;
        RECT 757.480 278.840 758.080 279.440 ;
    END
  END o_m_axi_arlen[6]
  PIN o_m_axi_arlen[7]
    DIRECTION OUTPUT ;
    USE SIGNAL ;
    ANTENNADIFFAREA 0.340600 ;
    PORT
      LAYER met3 ;
        RECT 757.480 282.240 758.080 282.840 ;
    END
  END o_m_axi_arlen[7]
  PIN o_m_axi_arvalid
    DIRECTION OUTPUT ;
    USE SIGNAL ;
    ANTENNADIFFAREA 0.340600 ;
    PORT
      LAYER met3 ;
        RECT 757.480 285.640 758.080 286.240 ;
    END
  END o_m_axi_arvalid
  PIN o_m_axi_awaddr[0]
    DIRECTION OUTPUT ;
    USE SIGNAL ;
    PORT
      LAYER met2 ;
        RECT 106.350 0.000 106.630 0.280 ;
    END
  END o_m_axi_awaddr[0]
  PIN o_m_axi_awaddr[10]
    DIRECTION OUTPUT ;
    USE SIGNAL ;
    ANTENNADIFFAREA 0.340600 ;
    PORT
      LAYER met2 ;
        RECT 170.750 0.000 171.030 0.280 ;
    END
  END o_m_axi_awaddr[10]
  PIN o_m_axi_awaddr[11]
    DIRECTION OUTPUT ;
    USE SIGNAL ;
    ANTENNADIFFAREA 0.340600 ;
    PORT
      LAYER met2 ;
        RECT 177.190 0.000 177.470 0.280 ;
    END
  END o_m_axi_awaddr[11]
  PIN o_m_axi_awaddr[12]
    DIRECTION OUTPUT ;
    USE SIGNAL ;
    ANTENNADIFFAREA 0.340600 ;
    PORT
      LAYER met2 ;
        RECT 183.630 0.000 183.910 0.280 ;
    END
  END o_m_axi_awaddr[12]
  PIN o_m_axi_awaddr[13]
    DIRECTION OUTPUT ;
    USE SIGNAL ;
    ANTENNADIFFAREA 0.340600 ;
    PORT
      LAYER met2 ;
        RECT 190.070 0.000 190.350 0.280 ;
    END
  END o_m_axi_awaddr[13]
  PIN o_m_axi_awaddr[14]
    DIRECTION OUTPUT ;
    USE SIGNAL ;
    ANTENNADIFFAREA 0.340600 ;
    PORT
      LAYER met2 ;
        RECT 196.510 0.000 196.790 0.280 ;
    END
  END o_m_axi_awaddr[14]
  PIN o_m_axi_awaddr[15]
    DIRECTION OUTPUT ;
    USE SIGNAL ;
    ANTENNADIFFAREA 0.340600 ;
    PORT
      LAYER met2 ;
        RECT 202.950 0.000 203.230 0.280 ;
    END
  END o_m_axi_awaddr[15]
  PIN o_m_axi_awaddr[16]
    DIRECTION OUTPUT ;
    USE SIGNAL ;
    ANTENNADIFFAREA 0.340600 ;
    PORT
      LAYER met2 ;
        RECT 209.390 0.000 209.670 0.280 ;
    END
  END o_m_axi_awaddr[16]
  PIN o_m_axi_awaddr[17]
    DIRECTION OUTPUT ;
    USE SIGNAL ;
    ANTENNADIFFAREA 0.340600 ;
    PORT
      LAYER met2 ;
        RECT 215.830 0.000 216.110 0.280 ;
    END
  END o_m_axi_awaddr[17]
  PIN o_m_axi_awaddr[18]
    DIRECTION OUTPUT ;
    USE SIGNAL ;
    ANTENNADIFFAREA 0.340600 ;
    PORT
      LAYER met2 ;
        RECT 222.270 0.000 222.550 0.280 ;
    END
  END o_m_axi_awaddr[18]
  PIN o_m_axi_awaddr[19]
    DIRECTION OUTPUT ;
    USE SIGNAL ;
    ANTENNADIFFAREA 0.340600 ;
    PORT
      LAYER met2 ;
        RECT 228.710 0.000 228.990 0.280 ;
    END
  END o_m_axi_awaddr[19]
  PIN o_m_axi_awaddr[1]
    DIRECTION OUTPUT ;
    USE SIGNAL ;
    PORT
      LAYER met2 ;
        RECT 112.790 0.000 113.070 0.280 ;
    END
  END o_m_axi_awaddr[1]
  PIN o_m_axi_awaddr[20]
    DIRECTION OUTPUT ;
    USE SIGNAL ;
    ANTENNADIFFAREA 0.340600 ;
    PORT
      LAYER met2 ;
        RECT 235.150 0.000 235.430 0.280 ;
    END
  END o_m_axi_awaddr[20]
  PIN o_m_axi_awaddr[21]
    DIRECTION OUTPUT ;
    USE SIGNAL ;
    ANTENNADIFFAREA 0.340600 ;
    PORT
      LAYER met2 ;
        RECT 241.590 0.000 241.870 0.280 ;
    END
  END o_m_axi_awaddr[21]
  PIN o_m_axi_awaddr[22]
    DIRECTION OUTPUT ;
    USE SIGNAL ;
    ANTENNADIFFAREA 0.340600 ;
    PORT
      LAYER met2 ;
        RECT 248.030 0.000 248.310 0.280 ;
    END
  END o_m_axi_awaddr[22]
  PIN o_m_axi_awaddr[23]
    DIRECTION OUTPUT ;
    USE SIGNAL ;
    ANTENNADIFFAREA 0.340600 ;
    PORT
      LAYER met2 ;
        RECT 254.470 0.000 254.750 0.280 ;
    END
  END o_m_axi_awaddr[23]
  PIN o_m_axi_awaddr[24]
    DIRECTION OUTPUT ;
    USE SIGNAL ;
    ANTENNADIFFAREA 0.340600 ;
    PORT
      LAYER met2 ;
        RECT 260.910 0.000 261.190 0.280 ;
    END
  END o_m_axi_awaddr[24]
  PIN o_m_axi_awaddr[25]
    DIRECTION OUTPUT ;
    USE SIGNAL ;
    ANTENNADIFFAREA 0.340600 ;
    PORT
      LAYER met2 ;
        RECT 267.350 0.000 267.630 0.280 ;
    END
  END o_m_axi_awaddr[25]
  PIN o_m_axi_awaddr[26]
    DIRECTION OUTPUT ;
    USE SIGNAL ;
    ANTENNADIFFAREA 0.340600 ;
    PORT
      LAYER met2 ;
        RECT 273.790 0.000 274.070 0.280 ;
    END
  END o_m_axi_awaddr[26]
  PIN o_m_axi_awaddr[27]
    DIRECTION OUTPUT ;
    USE SIGNAL ;
    ANTENNADIFFAREA 0.340600 ;
    PORT
      LAYER met2 ;
        RECT 280.230 0.000 280.510 0.280 ;
    END
  END o_m_axi_awaddr[27]
  PIN o_m_axi_awaddr[28]
    DIRECTION OUTPUT ;
    USE SIGNAL ;
    ANTENNADIFFAREA 0.340600 ;
    PORT
      LAYER met2 ;
        RECT 286.670 0.000 286.950 0.280 ;
    END
  END o_m_axi_awaddr[28]
  PIN o_m_axi_awaddr[29]
    DIRECTION OUTPUT ;
    USE SIGNAL ;
    ANTENNADIFFAREA 0.340600 ;
    PORT
      LAYER met2 ;
        RECT 293.110 0.000 293.390 0.280 ;
    END
  END o_m_axi_awaddr[29]
  PIN o_m_axi_awaddr[2]
    DIRECTION OUTPUT ;
    USE SIGNAL ;
    ANTENNADIFFAREA 0.340600 ;
    PORT
      LAYER met2 ;
        RECT 119.230 0.000 119.510 0.280 ;
    END
  END o_m_axi_awaddr[2]
  PIN o_m_axi_awaddr[30]
    DIRECTION OUTPUT ;
    USE SIGNAL ;
    ANTENNADIFFAREA 0.340600 ;
    PORT
      LAYER met2 ;
        RECT 299.550 0.000 299.830 0.280 ;
    END
  END o_m_axi_awaddr[30]
  PIN o_m_axi_awaddr[31]
    DIRECTION OUTPUT ;
    USE SIGNAL ;
    ANTENNADIFFAREA 0.340600 ;
    PORT
      LAYER met2 ;
        RECT 305.990 0.000 306.270 0.280 ;
    END
  END o_m_axi_awaddr[31]
  PIN o_m_axi_awaddr[3]
    DIRECTION OUTPUT ;
    USE SIGNAL ;
    ANTENNADIFFAREA 0.340600 ;
    PORT
      LAYER met2 ;
        RECT 125.670 0.000 125.950 0.280 ;
    END
  END o_m_axi_awaddr[3]
  PIN o_m_axi_awaddr[4]
    DIRECTION OUTPUT ;
    USE SIGNAL ;
    ANTENNADIFFAREA 0.340600 ;
    PORT
      LAYER met2 ;
        RECT 132.110 0.000 132.390 0.280 ;
    END
  END o_m_axi_awaddr[4]
  PIN o_m_axi_awaddr[5]
    DIRECTION OUTPUT ;
    USE SIGNAL ;
    ANTENNADIFFAREA 0.340600 ;
    PORT
      LAYER met2 ;
        RECT 138.550 0.000 138.830 0.280 ;
    END
  END o_m_axi_awaddr[5]
  PIN o_m_axi_awaddr[6]
    DIRECTION OUTPUT ;
    USE SIGNAL ;
    ANTENNADIFFAREA 0.340600 ;
    PORT
      LAYER met2 ;
        RECT 144.990 0.000 145.270 0.280 ;
    END
  END o_m_axi_awaddr[6]
  PIN o_m_axi_awaddr[7]
    DIRECTION OUTPUT ;
    USE SIGNAL ;
    ANTENNADIFFAREA 0.340600 ;
    PORT
      LAYER met2 ;
        RECT 151.430 0.000 151.710 0.280 ;
    END
  END o_m_axi_awaddr[7]
  PIN o_m_axi_awaddr[8]
    DIRECTION OUTPUT ;
    USE SIGNAL ;
    ANTENNADIFFAREA 0.340600 ;
    PORT
      LAYER met2 ;
        RECT 157.870 0.000 158.150 0.280 ;
    END
  END o_m_axi_awaddr[8]
  PIN o_m_axi_awaddr[9]
    DIRECTION OUTPUT ;
    USE SIGNAL ;
    ANTENNADIFFAREA 0.340600 ;
    PORT
      LAYER met2 ;
        RECT 164.310 0.000 164.590 0.280 ;
    END
  END o_m_axi_awaddr[9]
  PIN o_m_axi_awvalid
    DIRECTION OUTPUT ;
    USE SIGNAL ;
    ANTENNADIFFAREA 0.340600 ;
    PORT
      LAYER met2 ;
        RECT 312.430 0.000 312.710 0.280 ;
    END
  END o_m_axi_awvalid
  PIN o_m_axi_bready
    DIRECTION OUTPUT ;
    USE SIGNAL ;
    PORT
      LAYER met2 ;
        RECT 344.630 0.000 344.910 0.280 ;
    END
  END o_m_axi_bready
  PIN o_m_axi_rready
    DIRECTION OUTPUT ;
    USE SIGNAL ;
    ANTENNADIFFAREA 0.340600 ;
    PORT
      LAYER met3 ;
        RECT 757.480 292.440 758.080 293.040 ;
    END
  END o_m_axi_rready
  PIN o_m_axi_wdata[0]
    DIRECTION OUTPUT ;
    USE SIGNAL ;
    ANTENNADIFFAREA 0.340600 ;
    PORT
      LAYER met2 ;
        RECT 428.350 0.000 428.630 0.280 ;
    END
  END o_m_axi_wdata[0]
  PIN o_m_axi_wdata[10]
    DIRECTION OUTPUT ;
    USE SIGNAL ;
    ANTENNADIFFAREA 0.340600 ;
    PORT
      LAYER met2 ;
        RECT 492.750 0.000 493.030 0.280 ;
    END
  END o_m_axi_wdata[10]
  PIN o_m_axi_wdata[11]
    DIRECTION OUTPUT ;
    USE SIGNAL ;
    ANTENNADIFFAREA 0.340600 ;
    PORT
      LAYER met2 ;
        RECT 499.190 0.000 499.470 0.280 ;
    END
  END o_m_axi_wdata[11]
  PIN o_m_axi_wdata[12]
    DIRECTION OUTPUT ;
    USE SIGNAL ;
    ANTENNADIFFAREA 0.340600 ;
    PORT
      LAYER met2 ;
        RECT 505.630 0.000 505.910 0.280 ;
    END
  END o_m_axi_wdata[12]
  PIN o_m_axi_wdata[13]
    DIRECTION OUTPUT ;
    USE SIGNAL ;
    ANTENNADIFFAREA 0.340600 ;
    PORT
      LAYER met2 ;
        RECT 512.070 0.000 512.350 0.280 ;
    END
  END o_m_axi_wdata[13]
  PIN o_m_axi_wdata[14]
    DIRECTION OUTPUT ;
    USE SIGNAL ;
    ANTENNADIFFAREA 0.340600 ;
    PORT
      LAYER met2 ;
        RECT 518.510 0.000 518.790 0.280 ;
    END
  END o_m_axi_wdata[14]
  PIN o_m_axi_wdata[15]
    DIRECTION OUTPUT ;
    USE SIGNAL ;
    ANTENNADIFFAREA 0.340600 ;
    PORT
      LAYER met2 ;
        RECT 524.950 0.000 525.230 0.280 ;
    END
  END o_m_axi_wdata[15]
  PIN o_m_axi_wdata[16]
    DIRECTION OUTPUT ;
    USE SIGNAL ;
    ANTENNADIFFAREA 0.340600 ;
    PORT
      LAYER met2 ;
        RECT 531.390 0.000 531.670 0.280 ;
    END
  END o_m_axi_wdata[16]
  PIN o_m_axi_wdata[17]
    DIRECTION OUTPUT ;
    USE SIGNAL ;
    ANTENNADIFFAREA 0.340600 ;
    PORT
      LAYER met2 ;
        RECT 537.830 0.000 538.110 0.280 ;
    END
  END o_m_axi_wdata[17]
  PIN o_m_axi_wdata[18]
    DIRECTION OUTPUT ;
    USE SIGNAL ;
    ANTENNADIFFAREA 0.340600 ;
    PORT
      LAYER met2 ;
        RECT 544.270 0.000 544.550 0.280 ;
    END
  END o_m_axi_wdata[18]
  PIN o_m_axi_wdata[19]
    DIRECTION OUTPUT ;
    USE SIGNAL ;
    ANTENNADIFFAREA 0.340600 ;
    PORT
      LAYER met2 ;
        RECT 550.710 0.000 550.990 0.280 ;
    END
  END o_m_axi_wdata[19]
  PIN o_m_axi_wdata[1]
    DIRECTION OUTPUT ;
    USE SIGNAL ;
    ANTENNADIFFAREA 0.340600 ;
    PORT
      LAYER met2 ;
        RECT 434.790 0.000 435.070 0.280 ;
    END
  END o_m_axi_wdata[1]
  PIN o_m_axi_wdata[20]
    DIRECTION OUTPUT ;
    USE SIGNAL ;
    ANTENNADIFFAREA 0.340600 ;
    PORT
      LAYER met2 ;
        RECT 557.150 0.000 557.430 0.280 ;
    END
  END o_m_axi_wdata[20]
  PIN o_m_axi_wdata[21]
    DIRECTION OUTPUT ;
    USE SIGNAL ;
    ANTENNADIFFAREA 0.340600 ;
    PORT
      LAYER met2 ;
        RECT 563.590 0.000 563.870 0.280 ;
    END
  END o_m_axi_wdata[21]
  PIN o_m_axi_wdata[22]
    DIRECTION OUTPUT ;
    USE SIGNAL ;
    ANTENNADIFFAREA 0.340600 ;
    PORT
      LAYER met2 ;
        RECT 570.030 0.000 570.310 0.280 ;
    END
  END o_m_axi_wdata[22]
  PIN o_m_axi_wdata[23]
    DIRECTION OUTPUT ;
    USE SIGNAL ;
    ANTENNADIFFAREA 0.340600 ;
    PORT
      LAYER met2 ;
        RECT 576.470 0.000 576.750 0.280 ;
    END
  END o_m_axi_wdata[23]
  PIN o_m_axi_wdata[24]
    DIRECTION OUTPUT ;
    USE SIGNAL ;
    ANTENNADIFFAREA 0.340600 ;
    PORT
      LAYER met2 ;
        RECT 582.910 0.000 583.190 0.280 ;
    END
  END o_m_axi_wdata[24]
  PIN o_m_axi_wdata[25]
    DIRECTION OUTPUT ;
    USE SIGNAL ;
    ANTENNADIFFAREA 0.340600 ;
    PORT
      LAYER met2 ;
        RECT 589.350 0.000 589.630 0.280 ;
    END
  END o_m_axi_wdata[25]
  PIN o_m_axi_wdata[26]
    DIRECTION OUTPUT ;
    USE SIGNAL ;
    ANTENNADIFFAREA 0.340600 ;
    PORT
      LAYER met2 ;
        RECT 595.790 0.000 596.070 0.280 ;
    END
  END o_m_axi_wdata[26]
  PIN o_m_axi_wdata[27]
    DIRECTION OUTPUT ;
    USE SIGNAL ;
    ANTENNADIFFAREA 0.340600 ;
    PORT
      LAYER met2 ;
        RECT 602.230 0.000 602.510 0.280 ;
    END
  END o_m_axi_wdata[27]
  PIN o_m_axi_wdata[28]
    DIRECTION OUTPUT ;
    USE SIGNAL ;
    ANTENNADIFFAREA 0.340600 ;
    PORT
      LAYER met2 ;
        RECT 608.670 0.000 608.950 0.280 ;
    END
  END o_m_axi_wdata[28]
  PIN o_m_axi_wdata[29]
    DIRECTION OUTPUT ;
    USE SIGNAL ;
    ANTENNADIFFAREA 0.340600 ;
    PORT
      LAYER met2 ;
        RECT 615.110 0.000 615.390 0.280 ;
    END
  END o_m_axi_wdata[29]
  PIN o_m_axi_wdata[2]
    DIRECTION OUTPUT ;
    USE SIGNAL ;
    ANTENNADIFFAREA 0.340600 ;
    PORT
      LAYER met2 ;
        RECT 441.230 0.000 441.510 0.280 ;
    END
  END o_m_axi_wdata[2]
  PIN o_m_axi_wdata[30]
    DIRECTION OUTPUT ;
    USE SIGNAL ;
    ANTENNADIFFAREA 0.340600 ;
    PORT
      LAYER met2 ;
        RECT 621.550 0.000 621.830 0.280 ;
    END
  END o_m_axi_wdata[30]
  PIN o_m_axi_wdata[31]
    DIRECTION OUTPUT ;
    USE SIGNAL ;
    ANTENNADIFFAREA 0.340600 ;
    PORT
      LAYER met2 ;
        RECT 627.990 0.000 628.270 0.280 ;
    END
  END o_m_axi_wdata[31]
  PIN o_m_axi_wdata[3]
    DIRECTION OUTPUT ;
    USE SIGNAL ;
    ANTENNADIFFAREA 0.340600 ;
    PORT
      LAYER met2 ;
        RECT 447.670 0.000 447.950 0.280 ;
    END
  END o_m_axi_wdata[3]
  PIN o_m_axi_wdata[4]
    DIRECTION OUTPUT ;
    USE SIGNAL ;
    ANTENNADIFFAREA 0.340600 ;
    PORT
      LAYER met2 ;
        RECT 454.110 0.000 454.390 0.280 ;
    END
  END o_m_axi_wdata[4]
  PIN o_m_axi_wdata[5]
    DIRECTION OUTPUT ;
    USE SIGNAL ;
    ANTENNADIFFAREA 0.340600 ;
    PORT
      LAYER met2 ;
        RECT 460.550 0.000 460.830 0.280 ;
    END
  END o_m_axi_wdata[5]
  PIN o_m_axi_wdata[6]
    DIRECTION OUTPUT ;
    USE SIGNAL ;
    ANTENNADIFFAREA 0.340600 ;
    PORT
      LAYER met2 ;
        RECT 466.990 0.000 467.270 0.280 ;
    END
  END o_m_axi_wdata[6]
  PIN o_m_axi_wdata[7]
    DIRECTION OUTPUT ;
    USE SIGNAL ;
    ANTENNADIFFAREA 0.340600 ;
    PORT
      LAYER met2 ;
        RECT 473.430 0.000 473.710 0.280 ;
    END
  END o_m_axi_wdata[7]
  PIN o_m_axi_wdata[8]
    DIRECTION OUTPUT ;
    USE SIGNAL ;
    ANTENNADIFFAREA 0.340600 ;
    PORT
      LAYER met2 ;
        RECT 479.870 0.000 480.150 0.280 ;
    END
  END o_m_axi_wdata[8]
  PIN o_m_axi_wdata[9]
    DIRECTION OUTPUT ;
    USE SIGNAL ;
    ANTENNADIFFAREA 0.340600 ;
    PORT
      LAYER met2 ;
        RECT 486.310 0.000 486.590 0.280 ;
    END
  END o_m_axi_wdata[9]
  PIN o_m_axi_wlast
    DIRECTION OUTPUT ;
    USE SIGNAL ;
    ANTENNADIFFAREA 0.340600 ;
    PORT
      LAYER met2 ;
        RECT 634.430 0.000 634.710 0.280 ;
    END
  END o_m_axi_wlast
  PIN o_m_axi_wvalid
    DIRECTION OUTPUT ;
    USE SIGNAL ;
    ANTENNADIFFAREA 0.340600 ;
    PORT
      LAYER met2 ;
        RECT 640.870 0.000 641.150 0.280 ;
    END
  END o_m_axi_wvalid
  PIN o_s_axil_arready
    DIRECTION OUTPUT ;
    USE SIGNAL ;
    ANTENNADIFFAREA 0.340600 ;
    PORT
      LAYER met3 ;
        RECT 0.000 319.640 0.600 320.240 ;
    END
  END o_s_axil_arready
  PIN o_s_axil_awready
    DIRECTION OUTPUT ;
    USE SIGNAL ;
    ANTENNADIFFAREA 0.340600 ;
    PORT
      LAYER met3 ;
        RECT 0.000 142.840 0.600 143.440 ;
    END
  END o_s_axil_awready
  PIN o_s_axil_bresp[0]
    DIRECTION OUTPUT ;
    USE SIGNAL ;
    PORT
      LAYER met3 ;
        RECT 0.000 275.440 0.600 276.040 ;
    END
  END o_s_axil_bresp[0]
  PIN o_s_axil_bresp[1]
    DIRECTION OUTPUT ;
    USE SIGNAL ;
    PORT
      LAYER met3 ;
        RECT 0.000 278.840 0.600 279.440 ;
    END
  END o_s_axil_bresp[1]
  PIN o_s_axil_bvalid
    DIRECTION OUTPUT ;
    USE SIGNAL ;
    ANTENNADIFFAREA 0.340600 ;
    PORT
      LAYER met3 ;
        RECT 0.000 282.240 0.600 282.840 ;
    END
  END o_s_axil_bvalid
  PIN o_s_axil_rdata[0]
    DIRECTION OUTPUT ;
    USE SIGNAL ;
    ANTENNADIFFAREA 0.340600 ;
    PORT
      LAYER met3 ;
        RECT 0.000 323.040 0.600 323.640 ;
    END
  END o_s_axil_rdata[0]
  PIN o_s_axil_rdata[10]
    DIRECTION OUTPUT ;
    USE SIGNAL ;
    ANTENNADIFFAREA 0.340600 ;
    PORT
      LAYER met3 ;
        RECT 0.000 357.040 0.600 357.640 ;
    END
  END o_s_axil_rdata[10]
  PIN o_s_axil_rdata[11]
    DIRECTION OUTPUT ;
    USE SIGNAL ;
    ANTENNADIFFAREA 0.340600 ;
    PORT
      LAYER met3 ;
        RECT 0.000 360.440 0.600 361.040 ;
    END
  END o_s_axil_rdata[11]
  PIN o_s_axil_rdata[12]
    DIRECTION OUTPUT ;
    USE SIGNAL ;
    ANTENNADIFFAREA 0.340600 ;
    PORT
      LAYER met3 ;
        RECT 0.000 363.840 0.600 364.440 ;
    END
  END o_s_axil_rdata[12]
  PIN o_s_axil_rdata[13]
    DIRECTION OUTPUT ;
    USE SIGNAL ;
    ANTENNADIFFAREA 0.340600 ;
    PORT
      LAYER met3 ;
        RECT 0.000 367.240 0.600 367.840 ;
    END
  END o_s_axil_rdata[13]
  PIN o_s_axil_rdata[14]
    DIRECTION OUTPUT ;
    USE SIGNAL ;
    ANTENNADIFFAREA 0.340600 ;
    PORT
      LAYER met3 ;
        RECT 0.000 370.640 0.600 371.240 ;
    END
  END o_s_axil_rdata[14]
  PIN o_s_axil_rdata[15]
    DIRECTION OUTPUT ;
    USE SIGNAL ;
    ANTENNADIFFAREA 0.340600 ;
    PORT
      LAYER met3 ;
        RECT 0.000 374.040 0.600 374.640 ;
    END
  END o_s_axil_rdata[15]
  PIN o_s_axil_rdata[16]
    DIRECTION OUTPUT ;
    USE SIGNAL ;
    ANTENNADIFFAREA 0.340600 ;
    PORT
      LAYER met3 ;
        RECT 0.000 377.440 0.600 378.040 ;
    END
  END o_s_axil_rdata[16]
  PIN o_s_axil_rdata[17]
    DIRECTION OUTPUT ;
    USE SIGNAL ;
    ANTENNADIFFAREA 0.340600 ;
    PORT
      LAYER met3 ;
        RECT 0.000 380.840 0.600 381.440 ;
    END
  END o_s_axil_rdata[17]
  PIN o_s_axil_rdata[18]
    DIRECTION OUTPUT ;
    USE SIGNAL ;
    ANTENNADIFFAREA 0.340600 ;
    PORT
      LAYER met3 ;
        RECT 0.000 384.240 0.600 384.840 ;
    END
  END o_s_axil_rdata[18]
  PIN o_s_axil_rdata[19]
    DIRECTION OUTPUT ;
    USE SIGNAL ;
    ANTENNADIFFAREA 0.340600 ;
    PORT
      LAYER met3 ;
        RECT 0.000 387.640 0.600 388.240 ;
    END
  END o_s_axil_rdata[19]
  PIN o_s_axil_rdata[1]
    DIRECTION OUTPUT ;
    USE SIGNAL ;
    ANTENNADIFFAREA 0.340600 ;
    PORT
      LAYER met3 ;
        RECT 0.000 326.440 0.600 327.040 ;
    END
  END o_s_axil_rdata[1]
  PIN o_s_axil_rdata[20]
    DIRECTION OUTPUT ;
    USE SIGNAL ;
    ANTENNADIFFAREA 0.340600 ;
    PORT
      LAYER met3 ;
        RECT 0.000 391.040 0.600 391.640 ;
    END
  END o_s_axil_rdata[20]
  PIN o_s_axil_rdata[21]
    DIRECTION OUTPUT ;
    USE SIGNAL ;
    ANTENNADIFFAREA 0.340600 ;
    PORT
      LAYER met3 ;
        RECT 0.000 394.440 0.600 395.040 ;
    END
  END o_s_axil_rdata[21]
  PIN o_s_axil_rdata[22]
    DIRECTION OUTPUT ;
    USE SIGNAL ;
    ANTENNADIFFAREA 0.340600 ;
    PORT
      LAYER met3 ;
        RECT 0.000 397.840 0.600 398.440 ;
    END
  END o_s_axil_rdata[22]
  PIN o_s_axil_rdata[23]
    DIRECTION OUTPUT ;
    USE SIGNAL ;
    ANTENNADIFFAREA 0.340600 ;
    PORT
      LAYER met3 ;
        RECT 0.000 401.240 0.600 401.840 ;
    END
  END o_s_axil_rdata[23]
  PIN o_s_axil_rdata[24]
    DIRECTION OUTPUT ;
    USE SIGNAL ;
    ANTENNADIFFAREA 0.340600 ;
    PORT
      LAYER met3 ;
        RECT 0.000 404.640 0.600 405.240 ;
    END
  END o_s_axil_rdata[24]
  PIN o_s_axil_rdata[25]
    DIRECTION OUTPUT ;
    USE SIGNAL ;
    ANTENNADIFFAREA 0.340600 ;
    PORT
      LAYER met3 ;
        RECT 0.000 408.040 0.600 408.640 ;
    END
  END o_s_axil_rdata[25]
  PIN o_s_axil_rdata[26]
    DIRECTION OUTPUT ;
    USE SIGNAL ;
    ANTENNADIFFAREA 0.340600 ;
    PORT
      LAYER met3 ;
        RECT 0.000 411.440 0.600 412.040 ;
    END
  END o_s_axil_rdata[26]
  PIN o_s_axil_rdata[27]
    DIRECTION OUTPUT ;
    USE SIGNAL ;
    ANTENNADIFFAREA 0.340600 ;
    PORT
      LAYER met3 ;
        RECT 0.000 414.840 0.600 415.440 ;
    END
  END o_s_axil_rdata[27]
  PIN o_s_axil_rdata[28]
    DIRECTION OUTPUT ;
    USE SIGNAL ;
    ANTENNADIFFAREA 0.340600 ;
    PORT
      LAYER met3 ;
        RECT 0.000 418.240 0.600 418.840 ;
    END
  END o_s_axil_rdata[28]
  PIN o_s_axil_rdata[29]
    DIRECTION OUTPUT ;
    USE SIGNAL ;
    ANTENNADIFFAREA 0.340600 ;
    PORT
      LAYER met3 ;
        RECT 0.000 421.640 0.600 422.240 ;
    END
  END o_s_axil_rdata[29]
  PIN o_s_axil_rdata[2]
    DIRECTION OUTPUT ;
    USE SIGNAL ;
    ANTENNADIFFAREA 0.340600 ;
    PORT
      LAYER met3 ;
        RECT 0.000 329.840 0.600 330.440 ;
    END
  END o_s_axil_rdata[2]
  PIN o_s_axil_rdata[30]
    DIRECTION OUTPUT ;
    USE SIGNAL ;
    ANTENNADIFFAREA 0.340600 ;
    PORT
      LAYER met3 ;
        RECT 0.000 425.040 0.600 425.640 ;
    END
  END o_s_axil_rdata[30]
  PIN o_s_axil_rdata[31]
    DIRECTION OUTPUT ;
    USE SIGNAL ;
    ANTENNADIFFAREA 0.340600 ;
    PORT
      LAYER met3 ;
        RECT 0.000 428.440 0.600 429.040 ;
    END
  END o_s_axil_rdata[31]
  PIN o_s_axil_rdata[3]
    DIRECTION OUTPUT ;
    USE SIGNAL ;
    ANTENNADIFFAREA 0.340600 ;
    PORT
      LAYER met3 ;
        RECT 0.000 333.240 0.600 333.840 ;
    END
  END o_s_axil_rdata[3]
  PIN o_s_axil_rdata[4]
    DIRECTION OUTPUT ;
    USE SIGNAL ;
    ANTENNADIFFAREA 0.340600 ;
    PORT
      LAYER met3 ;
        RECT 0.000 336.640 0.600 337.240 ;
    END
  END o_s_axil_rdata[4]
  PIN o_s_axil_rdata[5]
    DIRECTION OUTPUT ;
    USE SIGNAL ;
    ANTENNADIFFAREA 0.340600 ;
    PORT
      LAYER met3 ;
        RECT 0.000 340.040 0.600 340.640 ;
    END
  END o_s_axil_rdata[5]
  PIN o_s_axil_rdata[6]
    DIRECTION OUTPUT ;
    USE SIGNAL ;
    ANTENNADIFFAREA 0.340600 ;
    PORT
      LAYER met3 ;
        RECT 0.000 343.440 0.600 344.040 ;
    END
  END o_s_axil_rdata[6]
  PIN o_s_axil_rdata[7]
    DIRECTION OUTPUT ;
    USE SIGNAL ;
    ANTENNADIFFAREA 0.340600 ;
    PORT
      LAYER met3 ;
        RECT 0.000 346.840 0.600 347.440 ;
    END
  END o_s_axil_rdata[7]
  PIN o_s_axil_rdata[8]
    DIRECTION OUTPUT ;
    USE SIGNAL ;
    ANTENNADIFFAREA 0.340600 ;
    PORT
      LAYER met3 ;
        RECT 0.000 350.240 0.600 350.840 ;
    END
  END o_s_axil_rdata[8]
  PIN o_s_axil_rdata[9]
    DIRECTION OUTPUT ;
    USE SIGNAL ;
    ANTENNADIFFAREA 0.340600 ;
    PORT
      LAYER met3 ;
        RECT 0.000 353.640 0.600 354.240 ;
    END
  END o_s_axil_rdata[9]
  PIN o_s_axil_rresp[0]
    DIRECTION OUTPUT ;
    USE SIGNAL ;
    PORT
      LAYER met3 ;
        RECT 0.000 431.840 0.600 432.440 ;
    END
  END o_s_axil_rresp[0]
  PIN o_s_axil_rresp[1]
    DIRECTION OUTPUT ;
    USE SIGNAL ;
    PORT
      LAYER met3 ;
        RECT 0.000 435.240 0.600 435.840 ;
    END
  END o_s_axil_rresp[1]
  PIN o_s_axil_rvalid
    DIRECTION OUTPUT ;
    USE SIGNAL ;
    ANTENNADIFFAREA 0.340600 ;
    PORT
      LAYER met3 ;
        RECT 0.000 438.640 0.600 439.240 ;
    END
  END o_s_axil_rvalid
  PIN o_s_axil_wready
    DIRECTION OUTPUT ;
    USE SIGNAL ;
    ANTENNADIFFAREA 0.340600 ;
    PORT
      LAYER met3 ;
        RECT 0.000 272.040 0.600 272.640 ;
    END
  END o_s_axil_wready
  PIN rstn
    DIRECTION INPUT ;
    USE SIGNAL ;
    ANTENNAGATEAREA 0.196500 ;
    PORT
      LAYER met2 ;
        RECT 396.150 0.000 396.430 0.280 ;
    END
  END rstn
  OBS
      LAYER nwell ;
        RECT 10.850 10.795 747.230 637.860 ;
      LAYER li1 ;
        RECT 11.040 10.795 747.040 637.645 ;
      LAYER met1 ;
        RECT 0.990 3.440 751.570 637.700 ;
      LAYER met2 ;
        RECT 1.010 0.560 751.550 637.700 ;
        RECT 1.010 0.070 106.070 0.560 ;
        RECT 106.910 0.070 112.510 0.560 ;
        RECT 113.350 0.070 118.950 0.560 ;
        RECT 119.790 0.070 125.390 0.560 ;
        RECT 126.230 0.070 131.830 0.560 ;
        RECT 132.670 0.070 138.270 0.560 ;
        RECT 139.110 0.070 144.710 0.560 ;
        RECT 145.550 0.070 151.150 0.560 ;
        RECT 151.990 0.070 157.590 0.560 ;
        RECT 158.430 0.070 164.030 0.560 ;
        RECT 164.870 0.070 170.470 0.560 ;
        RECT 171.310 0.070 176.910 0.560 ;
        RECT 177.750 0.070 183.350 0.560 ;
        RECT 184.190 0.070 189.790 0.560 ;
        RECT 190.630 0.070 196.230 0.560 ;
        RECT 197.070 0.070 202.670 0.560 ;
        RECT 203.510 0.070 209.110 0.560 ;
        RECT 209.950 0.070 215.550 0.560 ;
        RECT 216.390 0.070 221.990 0.560 ;
        RECT 222.830 0.070 228.430 0.560 ;
        RECT 229.270 0.070 234.870 0.560 ;
        RECT 235.710 0.070 241.310 0.560 ;
        RECT 242.150 0.070 247.750 0.560 ;
        RECT 248.590 0.070 254.190 0.560 ;
        RECT 255.030 0.070 260.630 0.560 ;
        RECT 261.470 0.070 267.070 0.560 ;
        RECT 267.910 0.070 273.510 0.560 ;
        RECT 274.350 0.070 279.950 0.560 ;
        RECT 280.790 0.070 286.390 0.560 ;
        RECT 287.230 0.070 292.830 0.560 ;
        RECT 293.670 0.070 299.270 0.560 ;
        RECT 300.110 0.070 305.710 0.560 ;
        RECT 306.550 0.070 312.150 0.560 ;
        RECT 312.990 0.070 318.590 0.560 ;
        RECT 319.430 0.070 325.030 0.560 ;
        RECT 325.870 0.070 331.470 0.560 ;
        RECT 332.310 0.070 337.910 0.560 ;
        RECT 338.750 0.070 344.350 0.560 ;
        RECT 345.190 0.070 376.550 0.560 ;
        RECT 377.390 0.070 395.870 0.560 ;
        RECT 396.710 0.070 428.070 0.560 ;
        RECT 428.910 0.070 434.510 0.560 ;
        RECT 435.350 0.070 440.950 0.560 ;
        RECT 441.790 0.070 447.390 0.560 ;
        RECT 448.230 0.070 453.830 0.560 ;
        RECT 454.670 0.070 460.270 0.560 ;
        RECT 461.110 0.070 466.710 0.560 ;
        RECT 467.550 0.070 473.150 0.560 ;
        RECT 473.990 0.070 479.590 0.560 ;
        RECT 480.430 0.070 486.030 0.560 ;
        RECT 486.870 0.070 492.470 0.560 ;
        RECT 493.310 0.070 498.910 0.560 ;
        RECT 499.750 0.070 505.350 0.560 ;
        RECT 506.190 0.070 511.790 0.560 ;
        RECT 512.630 0.070 518.230 0.560 ;
        RECT 519.070 0.070 524.670 0.560 ;
        RECT 525.510 0.070 531.110 0.560 ;
        RECT 531.950 0.070 537.550 0.560 ;
        RECT 538.390 0.070 543.990 0.560 ;
        RECT 544.830 0.070 550.430 0.560 ;
        RECT 551.270 0.070 556.870 0.560 ;
        RECT 557.710 0.070 563.310 0.560 ;
        RECT 564.150 0.070 569.750 0.560 ;
        RECT 570.590 0.070 576.190 0.560 ;
        RECT 577.030 0.070 582.630 0.560 ;
        RECT 583.470 0.070 589.070 0.560 ;
        RECT 589.910 0.070 595.510 0.560 ;
        RECT 596.350 0.070 601.950 0.560 ;
        RECT 602.790 0.070 608.390 0.560 ;
        RECT 609.230 0.070 614.830 0.560 ;
        RECT 615.670 0.070 621.270 0.560 ;
        RECT 622.110 0.070 627.710 0.560 ;
        RECT 628.550 0.070 634.150 0.560 ;
        RECT 634.990 0.070 640.590 0.560 ;
        RECT 641.430 0.070 647.030 0.560 ;
        RECT 647.870 0.070 751.550 0.560 ;
      LAYER met3 ;
        RECT 0.600 443.040 757.480 637.585 ;
        RECT 1.000 441.640 757.480 443.040 ;
        RECT 0.600 439.640 757.480 441.640 ;
        RECT 1.000 438.240 757.480 439.640 ;
        RECT 0.600 436.240 757.480 438.240 ;
        RECT 1.000 434.840 757.480 436.240 ;
        RECT 0.600 432.840 757.480 434.840 ;
        RECT 1.000 431.440 757.480 432.840 ;
        RECT 0.600 429.440 757.480 431.440 ;
        RECT 1.000 428.040 757.480 429.440 ;
        RECT 0.600 426.040 757.480 428.040 ;
        RECT 1.000 424.640 757.480 426.040 ;
        RECT 0.600 422.640 757.480 424.640 ;
        RECT 1.000 421.240 757.480 422.640 ;
        RECT 0.600 419.240 757.480 421.240 ;
        RECT 1.000 417.840 757.480 419.240 ;
        RECT 0.600 415.840 757.480 417.840 ;
        RECT 1.000 414.440 757.080 415.840 ;
        RECT 0.600 412.440 757.480 414.440 ;
        RECT 1.000 411.040 757.080 412.440 ;
        RECT 0.600 409.040 757.480 411.040 ;
        RECT 1.000 407.640 757.080 409.040 ;
        RECT 0.600 405.640 757.480 407.640 ;
        RECT 1.000 404.240 757.080 405.640 ;
        RECT 0.600 402.240 757.480 404.240 ;
        RECT 1.000 400.840 757.080 402.240 ;
        RECT 0.600 398.840 757.480 400.840 ;
        RECT 1.000 397.440 757.080 398.840 ;
        RECT 0.600 395.440 757.480 397.440 ;
        RECT 1.000 394.040 757.080 395.440 ;
        RECT 0.600 392.040 757.480 394.040 ;
        RECT 1.000 390.640 757.080 392.040 ;
        RECT 0.600 388.640 757.480 390.640 ;
        RECT 1.000 387.240 757.080 388.640 ;
        RECT 0.600 385.240 757.480 387.240 ;
        RECT 1.000 383.840 757.080 385.240 ;
        RECT 0.600 381.840 757.480 383.840 ;
        RECT 1.000 380.440 757.080 381.840 ;
        RECT 0.600 378.440 757.480 380.440 ;
        RECT 1.000 377.040 757.080 378.440 ;
        RECT 0.600 375.040 757.480 377.040 ;
        RECT 1.000 373.640 757.080 375.040 ;
        RECT 0.600 371.640 757.480 373.640 ;
        RECT 1.000 370.240 757.080 371.640 ;
        RECT 0.600 368.240 757.480 370.240 ;
        RECT 1.000 366.840 757.080 368.240 ;
        RECT 0.600 364.840 757.480 366.840 ;
        RECT 1.000 363.440 757.080 364.840 ;
        RECT 0.600 361.440 757.480 363.440 ;
        RECT 1.000 360.040 757.080 361.440 ;
        RECT 0.600 358.040 757.480 360.040 ;
        RECT 1.000 356.640 757.080 358.040 ;
        RECT 0.600 354.640 757.480 356.640 ;
        RECT 1.000 353.240 757.080 354.640 ;
        RECT 0.600 351.240 757.480 353.240 ;
        RECT 1.000 349.840 757.080 351.240 ;
        RECT 0.600 347.840 757.480 349.840 ;
        RECT 1.000 346.440 757.080 347.840 ;
        RECT 0.600 344.440 757.480 346.440 ;
        RECT 1.000 343.040 757.080 344.440 ;
        RECT 0.600 341.040 757.480 343.040 ;
        RECT 1.000 339.640 757.080 341.040 ;
        RECT 0.600 337.640 757.480 339.640 ;
        RECT 1.000 336.240 757.080 337.640 ;
        RECT 0.600 334.240 757.480 336.240 ;
        RECT 1.000 332.840 757.080 334.240 ;
        RECT 0.600 330.840 757.480 332.840 ;
        RECT 1.000 329.440 757.080 330.840 ;
        RECT 0.600 327.440 757.480 329.440 ;
        RECT 1.000 326.040 757.080 327.440 ;
        RECT 0.600 324.040 757.480 326.040 ;
        RECT 1.000 322.640 757.080 324.040 ;
        RECT 0.600 320.640 757.480 322.640 ;
        RECT 1.000 319.240 757.080 320.640 ;
        RECT 0.600 317.240 757.480 319.240 ;
        RECT 1.000 315.840 757.080 317.240 ;
        RECT 0.600 313.840 757.480 315.840 ;
        RECT 1.000 312.440 757.080 313.840 ;
        RECT 0.600 310.440 757.480 312.440 ;
        RECT 1.000 309.040 757.080 310.440 ;
        RECT 0.600 307.040 757.480 309.040 ;
        RECT 1.000 305.640 757.080 307.040 ;
        RECT 0.600 303.640 757.480 305.640 ;
        RECT 1.000 302.240 757.080 303.640 ;
        RECT 0.600 300.240 757.480 302.240 ;
        RECT 1.000 298.840 757.080 300.240 ;
        RECT 0.600 296.840 757.480 298.840 ;
        RECT 1.000 295.440 757.080 296.840 ;
        RECT 0.600 293.440 757.480 295.440 ;
        RECT 1.000 292.040 757.080 293.440 ;
        RECT 0.600 290.040 757.480 292.040 ;
        RECT 1.000 288.640 757.080 290.040 ;
        RECT 0.600 286.640 757.480 288.640 ;
        RECT 1.000 285.240 757.080 286.640 ;
        RECT 0.600 283.240 757.480 285.240 ;
        RECT 1.000 281.840 757.080 283.240 ;
        RECT 0.600 279.840 757.480 281.840 ;
        RECT 1.000 278.440 757.080 279.840 ;
        RECT 0.600 276.440 757.480 278.440 ;
        RECT 1.000 275.040 757.080 276.440 ;
        RECT 0.600 273.040 757.480 275.040 ;
        RECT 1.000 271.640 757.080 273.040 ;
        RECT 0.600 269.640 757.480 271.640 ;
        RECT 1.000 268.240 757.080 269.640 ;
        RECT 0.600 266.240 757.480 268.240 ;
        RECT 1.000 264.840 757.080 266.240 ;
        RECT 0.600 262.840 757.480 264.840 ;
        RECT 1.000 261.440 757.080 262.840 ;
        RECT 0.600 259.440 757.480 261.440 ;
        RECT 1.000 258.040 757.080 259.440 ;
        RECT 0.600 256.040 757.480 258.040 ;
        RECT 1.000 254.640 757.080 256.040 ;
        RECT 0.600 252.640 757.480 254.640 ;
        RECT 1.000 251.240 757.080 252.640 ;
        RECT 0.600 249.240 757.480 251.240 ;
        RECT 1.000 247.840 757.080 249.240 ;
        RECT 0.600 245.840 757.480 247.840 ;
        RECT 1.000 244.440 757.080 245.840 ;
        RECT 0.600 242.440 757.480 244.440 ;
        RECT 1.000 241.040 757.080 242.440 ;
        RECT 0.600 239.040 757.480 241.040 ;
        RECT 1.000 237.640 757.080 239.040 ;
        RECT 0.600 235.640 757.480 237.640 ;
        RECT 1.000 234.240 757.080 235.640 ;
        RECT 0.600 232.240 757.480 234.240 ;
        RECT 1.000 230.840 757.080 232.240 ;
        RECT 0.600 228.840 757.480 230.840 ;
        RECT 1.000 227.440 757.080 228.840 ;
        RECT 0.600 225.440 757.480 227.440 ;
        RECT 1.000 224.040 757.080 225.440 ;
        RECT 0.600 222.040 757.480 224.040 ;
        RECT 1.000 220.640 757.080 222.040 ;
        RECT 0.600 218.640 757.480 220.640 ;
        RECT 1.000 217.240 757.080 218.640 ;
        RECT 0.600 215.240 757.480 217.240 ;
        RECT 1.000 213.840 757.080 215.240 ;
        RECT 0.600 211.840 757.480 213.840 ;
        RECT 1.000 210.440 757.080 211.840 ;
        RECT 0.600 208.440 757.480 210.440 ;
        RECT 1.000 207.040 757.080 208.440 ;
        RECT 0.600 205.040 757.480 207.040 ;
        RECT 1.000 203.640 757.080 205.040 ;
        RECT 0.600 201.640 757.480 203.640 ;
        RECT 1.000 200.240 757.080 201.640 ;
        RECT 0.600 198.240 757.480 200.240 ;
        RECT 1.000 196.840 757.080 198.240 ;
        RECT 0.600 194.840 757.480 196.840 ;
        RECT 1.000 193.440 757.080 194.840 ;
        RECT 0.600 191.440 757.480 193.440 ;
        RECT 1.000 190.040 757.080 191.440 ;
        RECT 0.600 188.040 757.480 190.040 ;
        RECT 1.000 186.640 757.080 188.040 ;
        RECT 0.600 184.640 757.480 186.640 ;
        RECT 1.000 183.240 757.080 184.640 ;
        RECT 0.600 181.240 757.480 183.240 ;
        RECT 1.000 179.840 757.080 181.240 ;
        RECT 0.600 177.840 757.480 179.840 ;
        RECT 1.000 176.440 757.080 177.840 ;
        RECT 0.600 174.440 757.480 176.440 ;
        RECT 1.000 173.040 757.080 174.440 ;
        RECT 0.600 171.040 757.480 173.040 ;
        RECT 1.000 169.640 757.080 171.040 ;
        RECT 0.600 167.640 757.480 169.640 ;
        RECT 1.000 166.240 757.080 167.640 ;
        RECT 0.600 164.240 757.480 166.240 ;
        RECT 1.000 162.840 757.080 164.240 ;
        RECT 0.600 160.840 757.480 162.840 ;
        RECT 1.000 159.440 757.080 160.840 ;
        RECT 0.600 157.440 757.480 159.440 ;
        RECT 1.000 156.040 757.080 157.440 ;
        RECT 0.600 154.040 757.480 156.040 ;
        RECT 1.000 152.640 757.080 154.040 ;
        RECT 0.600 150.640 757.480 152.640 ;
        RECT 1.000 149.240 757.080 150.640 ;
        RECT 0.600 147.240 757.480 149.240 ;
        RECT 1.000 145.840 757.480 147.240 ;
        RECT 0.600 143.840 757.480 145.840 ;
        RECT 1.000 142.440 757.480 143.840 ;
        RECT 0.600 140.440 757.480 142.440 ;
        RECT 1.000 139.040 757.480 140.440 ;
        RECT 0.600 137.040 757.480 139.040 ;
        RECT 1.000 135.640 757.480 137.040 ;
        RECT 0.600 133.640 757.480 135.640 ;
        RECT 1.000 132.240 757.480 133.640 ;
        RECT 0.600 130.240 757.480 132.240 ;
        RECT 1.000 128.840 757.480 130.240 ;
        RECT 0.600 126.840 757.480 128.840 ;
        RECT 1.000 125.440 757.480 126.840 ;
        RECT 0.600 123.440 757.480 125.440 ;
        RECT 1.000 122.040 757.480 123.440 ;
        RECT 0.600 120.040 757.480 122.040 ;
        RECT 1.000 118.640 757.480 120.040 ;
        RECT 0.600 116.640 757.480 118.640 ;
        RECT 1.000 115.240 757.480 116.640 ;
        RECT 0.600 113.240 757.480 115.240 ;
        RECT 1.000 111.840 757.480 113.240 ;
        RECT 0.600 10.715 757.480 111.840 ;
      LAYER met4 ;
        RECT 13.175 12.415 70.975 452.025 ;
        RECT 73.375 12.415 74.275 452.025 ;
        RECT 76.675 12.415 218.175 452.025 ;
        RECT 220.575 12.415 221.475 452.025 ;
        RECT 223.875 12.415 365.375 452.025 ;
        RECT 367.775 12.415 368.675 452.025 ;
        RECT 371.075 12.415 512.575 452.025 ;
        RECT 514.975 12.415 515.875 452.025 ;
        RECT 518.275 12.415 659.775 452.025 ;
        RECT 662.175 12.415 663.075 452.025 ;
        RECT 665.475 12.415 720.985 452.025 ;
      LAYER met5 ;
        RECT 140.420 281.780 705.060 434.300 ;
        RECT 140.420 104.980 705.060 273.680 ;
        RECT 140.420 55.300 705.060 96.880 ;
  END
END top
END LIBRARY

